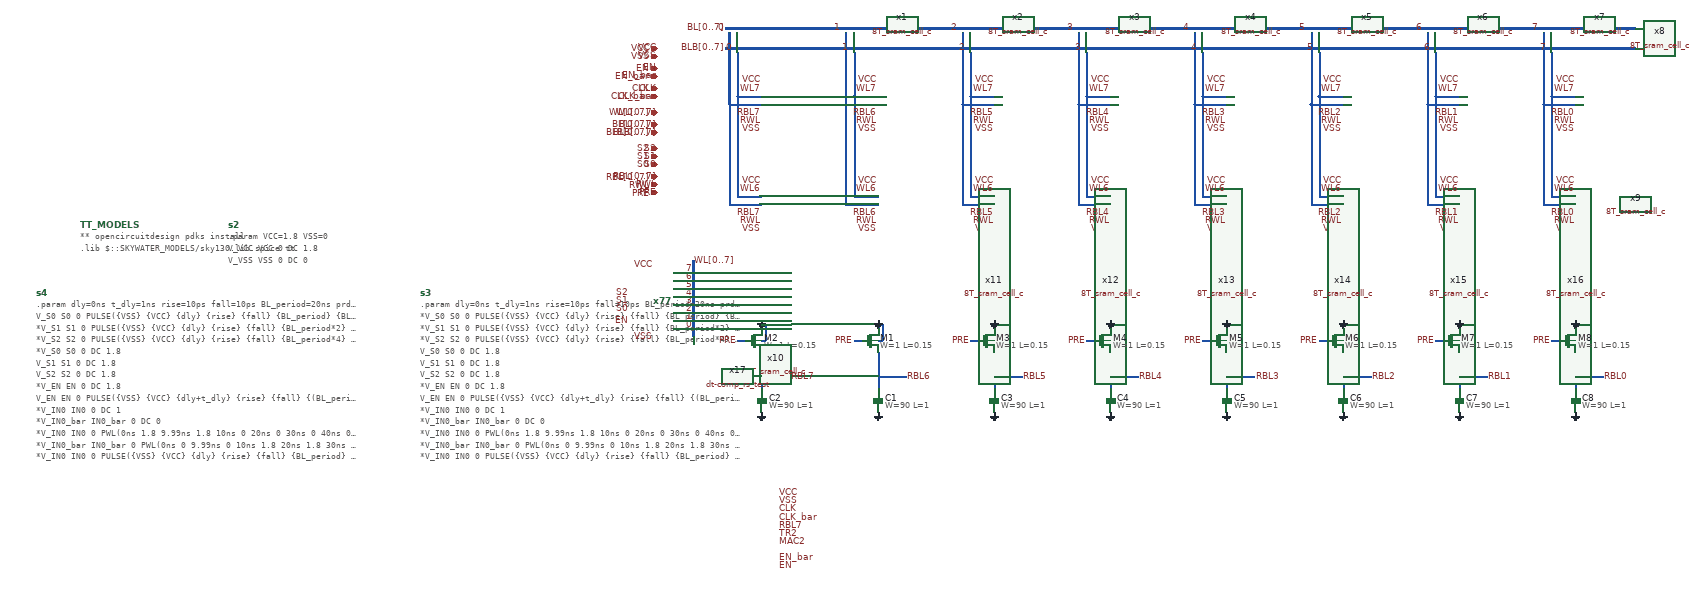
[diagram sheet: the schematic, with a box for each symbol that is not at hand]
v {xschem version=3.4.8RC file_version=1.3}
G {}
K {}
V {}
S {}
F {}
E {}
B 2 -940 -2980 -140 -2580 {flags=graph
y1=-0.027
y2=1.9
ypos1=-0.31605
ypos2=1.61095
divy=5
subdivy=1
unity=1
x1=-1.3514731e+246
x2=2.0890986e+307
divx=5
subdivx=1
xlabmag=1.0
ylabmag=1.0
dataset=-1
unitx=1
logx=0
logy=0
rawfile=$netlist_dir/write_test_row.raw
autoload=0
digital=1
legend=1
color="4 5 6 7 8 9 10 20 4 4 4 4 4 4 4 4"
node="x8.q
x7.q
x6.q
x5.q
x4.q
x3.q
x2.q
x1.q
x8.q_bar
x7.q_bar
x6.q_bar
x5.q_bar
x4.q_bar
x3.q_bar
x2.q_bar
x1.q_bar"
sim_type=tran}
B 2 -1760 -2980 -960 -2580 {flags=graph
y1=-0.027
y2=1.9
ypos1=-0.4124
ypos2=1.5146
divy=5
subdivy=1
unity=1
x1=-1.3514731e+246
x2=2.0890986e+307
divx=5
subdivx=1
xlabmag=1.0
ylabmag=1.0
dataset=-1
unitx=1
logx=0
logy=0
rawfile=$netlist_dir/write_test_row.raw
autoload=0
digital=1
color="4 5 6 7 8 9"
node="s2
s1
s0
en
pre
rwl"
hilight_wave=-1}
B 2 -1760 -2440 -960 -2040 {flags=graph
y1=-0.027
y2=1.9
ypos1=-0.027
ypos2=1.9
divy=5
subdivy=1
unity=1
x1=-1.3514731e+246
x2=2.0890986e+307
divx=5
subdivx=1
xlabmag=1.0
ylabmag=1.0
dataset=-1
unitx=1
logx=0
logy=0
rawfile=$netlist_dir/write_test_row.raw
autoload=0
digital=1
color="4 5 6 7 8 9 10 11"
node="bl7
bl6
bl5
bl4
bl3
bl2
bl1
bl0"
hilight_wave=-1}
B 2 -940 -2440 -140 -2040 {flags=graph
y1=-3.4e+249
y2=2.1e+307
ypos1=-0.027
ypos2=1.9
divy=5
subdivy=1
unity=1
x1=-1.3514731e+246
x2=2.0890986e+307
divx=5
subdivx=1
xlabmag=1.0
ylabmag=1.0
dataset=-1
unitx=1
logx=0
logy=0
rawfile=$netlist_dir/write_test_row.raw
autoload=0
digital=0
hilight_wave=2
color="4 5 6"
node="pre
rwl
rbl7"}
N 370 -1440 370 -1350 {lab=RBL7}
N 370 -1380 440 -1380 {lab=RBL7}
N 370 -1520 370 -1500 {lab=GND}
N 370 -1470 380 -1470 {lab=GND}
N 380 -1510 380 -1470 {lab=GND}
N 370 -1510 380 -1510 {lab=GND}
N 310 -1470 330 -1470 {lab=PRE}
N 280 -2250 2550 -2250 {lab=BL[0..7]
bus=true}
N 280 -2200 2550 -2200 {lab=BLB[0..7]
bus=true}
N 310 -2190 310 -2080 {lab=BLB0}
N 310 -2080 370 -2080 {lab=BLB0}
N 290 -2240 290 -2060 {lab=BL0
bus}
N 290 -2060 370 -2060 {lab=BL0}
N 600 -2190 600 -2080 {lab=BLB1}
N 600 -2080 660 -2080 {lab=BLB1}
N 580 -2240 580 -2060 {lab=BL1}
N 580 -2060 660 -2060 {lab=BL1}
N 890 -2190 890 -2080 {lab=BLB2}
N 890 -2080 950 -2080 {lab=BLB2}
N 870 -2240 870 -2060 {lab=BL2}
N 870 -2060 950 -2060 {lab=BL2}
N 1180 -2190 1180 -2080 {lab=BLB3}
N 1180 -2080 1240 -2080 {lab=BLB3}
N 1160 -2240 1160 -2060 {lab=BL3}
N 1160 -2060 1240 -2060 {lab=BL3}
N 1470 -2190 1470 -2080 {lab=BLB4}
N 1470 -2080 1530 -2080 {lab=BLB4}
N 1450 -2240 1450 -2060 {lab=BL4}
N 1450 -2060 1530 -2060 {lab=BL4}
N 1760 -2190 1760 -2080 {lab=BLB5}
N 1760 -2080 1820 -2080 {lab=BLB5}
N 1740 -2240 1740 -2060 {lab=BL5}
N 1740 -2060 1820 -2060 {lab=BL5}
N 2050 -2190 2050 -2080 {lab=BLB6}
N 2050 -2080 2110 -2080 {lab=BLB6}
N 2030 -2240 2030 -2060 {lab=BL6}
N 2030 -2060 2110 -2060 {lab=BL6}
N 2340 -2190 2340 -2080 {lab=BLB7}
N 2340 -2080 2400 -2080 {lab=BLB7}
N 2320 -2240 2320 -2060 {lab=BL7}
N 2320 -2060 2400 -2060 {lab=BL7}
N 200 -1670 200 -1480 {lab=WL[0..7]
bus=true}
N 150 -1640 190 -1640 {lab=WL7}
N 150 -1620 190 -1620 {lab=WL6}
N 150 -1600 190 -1600 {lab=WL5}
N 150 -1580 190 -1580 {lab=WL4}
N 150 -1560 190 -1560 {lab=WL3}
N 150 -1540 190 -1540 {lab=WL2}
N 150 -1520 190 -1520 {lab=WL1}
N 150 -1500 190 -1500 {lab=WL0}
N 290 -2060 290 -1810 {lab=BL0}
N 290 -1810 370 -1810 {lab=BL0}
N 310 -2080 310 -1830 {lab=BLB0}
N 310 -1830 370 -1830 {lab=BLB0}
N 580 -2060 580 -1810 {lab=BL1}
N 580 -1810 660 -1810 {lab=BL1}
N 600 -2080 600 -1830 {lab=BLB1}
N 600 -1830 660 -1830 {lab=BLB1}
N 870 -2060 870 -1810 {lab=BL2}
N 870 -1810 950 -1810 {lab=BL2}
N 890 -2080 890 -1830 {lab=BLB2}
N 890 -1830 950 -1830 {lab=BLB2}
N 1160 -2060 1160 -1810 {lab=BL3}
N 1160 -1810 1240 -1810 {lab=BL3}
N 1180 -2080 1180 -1830 {lab=BLB3}
N 1180 -1830 1240 -1830 {lab=BLB3}
N 1450 -2060 1450 -1810 {lab=BL4}
N 1450 -1810 1530 -1810 {lab=BL4}
N 1470 -2080 1470 -1830 {lab=BLB4}
N 1470 -1830 1530 -1830 {lab=BLB4}
N 1740 -2060 1740 -1810 {lab=BL5}
N 1740 -1810 1820 -1810 {lab=BL5}
N 1760 -2080 1760 -1830 {lab=BLB5}
N 1760 -1830 1820 -1830 {lab=BLB5}
N 2030 -2060 2030 -1810 {lab=BL6}
N 2030 -1810 2110 -1810 {lab=BL6}
N 2050 -2080 2050 -1830 {lab=BLB6}
N 2050 -1830 2110 -1830 {lab=BLB6}
N 2320 -2060 2320 -1810 {lab=BL7}
N 2320 -1810 2400 -1810 {lab=BL7}
N 2340 -2080 2340 -1830 {lab=BLB7}
N 2340 -1830 2400 -1830 {lab=BLB7}
N 660 -1440 660 -1350 {lab=RBL6}
N 660 -1380 730 -1380 {lab=RBL6}
N 660 -1520 660 -1500 {lab=GND}
N 660 -1470 670 -1470 {lab=GND}
N 670 -1510 670 -1470 {lab=GND}
N 660 -1510 670 -1510 {lab=GND}
N 600 -1470 620 -1470 {lab=PRE}
N 950 -1440 950 -1350 {lab=RBL5}
N 950 -1380 1020 -1380 {lab=RBL5}
N 950 -1520 950 -1500 {lab=GND}
N 950 -1470 960 -1470 {lab=GND}
N 960 -1510 960 -1470 {lab=GND}
N 950 -1510 960 -1510 {lab=GND}
N 890 -1470 910 -1470 {lab=PRE}
N 1240 -1440 1240 -1350 {lab=RBL4}
N 1240 -1380 1310 -1380 {lab=RBL4}
N 1240 -1520 1240 -1500 {lab=GND}
N 1240 -1470 1250 -1470 {lab=GND}
N 1250 -1510 1250 -1470 {lab=GND}
N 1240 -1510 1250 -1510 {lab=GND}
N 1180 -1470 1200 -1470 {lab=PRE}
N 1530 -1440 1530 -1350 {lab=RBL3}
N 1530 -1380 1600 -1380 {lab=RBL3}
N 1530 -1520 1530 -1500 {lab=GND}
N 1530 -1470 1540 -1470 {lab=GND}
N 1540 -1510 1540 -1470 {lab=GND}
N 1530 -1510 1540 -1510 {lab=GND}
N 1470 -1470 1490 -1470 {lab=PRE}
N 1820 -1440 1820 -1350 {lab=RBL2}
N 1820 -1380 1890 -1380 {lab=RBL2}
N 1820 -1520 1820 -1500 {lab=GND}
N 1820 -1470 1830 -1470 {lab=GND}
N 1830 -1510 1830 -1470 {lab=GND}
N 1820 -1510 1830 -1510 {lab=GND}
N 1760 -1470 1780 -1470 {lab=PRE}
N 2110 -1440 2110 -1350 {lab=RBL1}
N 2110 -1380 2180 -1380 {lab=RBL1}
N 2110 -1520 2110 -1500 {lab=GND}
N 2110 -1470 2120 -1470 {lab=GND}
N 2120 -1510 2120 -1470 {lab=GND}
N 2110 -1510 2120 -1510 {lab=GND}
N 2050 -1470 2070 -1470 {lab=PRE}
N 2400 -1440 2400 -1350 {lab=RBL0}
N 2400 -1380 2470 -1380 {lab=RBL0}
N 2400 -1520 2400 -1500 {lab=GND}
N 2400 -1470 2410 -1470 {lab=GND}
N 2410 -1510 2410 -1470 {lab=GND}
N 2400 -1510 2410 -1510 {lab=GND}
N 2340 -1470 2360 -1470 {lab=PRE}
C {iopin.sym} 110 -2040 0 0 {name=p7 lab=WL[0..7]}
C {lab_pin.sym} 110 -2040 0 0 {name=p18 sig_type=std_logic lab=WL[0..7]}
C {lab_pin.sym} 370 -2100 0 0 {name=p1 sig_type=std_logic lab=WL7}
C {lab_pin.sym} 370 -2000 0 0 {name=p43 sig_type=std_logic lab=VSS}
C {lab_pin.sym} 370 -2120 0 0 {name=p51 sig_type=std_logic lab=VCC}
C {code.sym} -1330 -1760 0 0 {
name=TT_MODELS
only_toplevel=true
format="tcleval( @value )"
spice_ignore=false
value="
** opencircuitdesign pdks install
.lib $::SKYWATER_MODELS/sky130.lib.spice tt
"
spice_ignore=false
      }
C {code_shown.sym} -960 -1760 0 1 {name=s2 only_toplevel=false spice_ignore=false value=
"
.param VCC=1.8 VSS=0

V_VCC VCC 0 DC 1.8
V_VSS VSS 0 DC 0
"}
C {iopin.sym} 110 -1950 0 0 {name=p69 lab=S2}
C {iopin.sym} 110 -1930 0 0 {name=p70 lab=S1}
C {iopin.sym} 110 -1910 0 0 {name=p71 lab=S0}
C {lab_pin.sym} 110 -1950 0 0 {name=p72 sig_type=std_logic lab=S2}
C {lab_pin.sym} 110 -1930 0 0 {name=p73 sig_type=std_logic lab=S1}
C {lab_pin.sym} 110 -1910 0 0 {name=p74 sig_type=std_logic lab=S0}
C {iopin.sym} 110 -2200 0 0 {name=p78 lab=VCC}
C {iopin.sym} 110 -2180 0 0 {name=p79 lab=VSS}
C {lab_pin.sym} 110 -2180 0 0 {name=p80 sig_type=std_logic lab=VSS}
C {lab_pin.sym} 110 -2200 0 0 {name=p81 sig_type=std_logic lab=VCC}
C {iopin.sym} 110 -2150 0 0 {name=p82 lab=EN}
C {lab_pin.sym} 110 -2150 0 0 {name=p83 sig_type=std_logic lab=EN}
C {code_shown.sym} -480 -1590 0 1 {name=s3 only_toplevel=false spice_ignore=true value=
"
.param dly=0ns t_dly=1ns rise=10ps fall=10ps BL_period=20ns prds=8 pre_time=6ns read_time=2ns write_delay=10ns 


*V_S0 S0 0 PULSE(\{VSS\} \{VCC\} \{dly\} \{rise\} \{fall\} \{BL_period\} \{BL_period*2\} \{prds\})
*V_S1 S1 0 PULSE(\{VSS\} \{VCC\} \{dly\} \{rise\} \{fall\} \{BL_period*2\} \{BL_period*4\} \{prds\})
*V_S2 S2 0 PULSE(\{VSS\} \{VCC\} \{dly\} \{rise\} \{fall\} \{BL_period*4\} \{BL_period*8\} \{prds\})

V_S0 S0 0 DC 1.8
V_S1 S1 0 DC 1.8
V_S2 S2 0 DC 1.8

*V_EN EN 0 DC 1.8
V_EN EN 0 PULSE(\{VSS\} \{VCC\} \{dly+t_dly\} \{rise\} \{fall\} \{(BL_period/2)-t_dly*2\} \{BL_period\} \{prds\})

*V_IN0 IN0 0 DC 1
*V_IN0_bar IN0_bar 0 DC 0
*V_IN0 IN0 0 PWL(0ns 1.8 9.99ns 1.8 10ns 0 20ns 0 30ns 0 40ns 0 50ns 0 60ns 0 69.99ns 0 70ns 1.8)
*V_IN0_bar IN0_bar 0 PWL(0ns 0 9.99ns 0 10ns 1.8 20ns 1.8 30ns 1.8 40ns 1.8 50ns 1.8 60ns 1.8 69.99ns 1.8 70ns 0)
*V_IN0 IN0 0 PULSE(\{VSS\} \{VCC\} \{dly\} \{rise\} \{fall\} \{BL_period\} \{BL_period*2\} \{prds\})
*V_IN0_bar IN0_bar 0 PULSE(\{VCC\} \{VSS\} \{dly\} \{rise\} \{fall\} \{BL_period\} \{BL_period*2\} \{prds\})

V_BL0 BLB0 0 PULSE(\{VSS\} \{VCC\} \{dly\} \{rise\} \{fall\} \{BL_period\} \{BL_period*2\} \{prds\})
V_BLB0 BL0 0 PULSE(\{VCC\} \{VSS\} \{dly\} \{rise\} \{fall\} \{BL_period\} \{BL_period*2\} \{prds\})

V_BL1 BLB1 0 PULSE(\{VSS\} \{VCC\} \{dly\} \{rise\} \{fall\} \{BL_period*2\} \{BL_period*4\} \{prds\})
V_BLB1 BL1 0 PULSE(\{VCC\} \{VSS\} \{dly\} \{rise\} \{fall\} \{BL_period*2\} \{BL_period*4\} \{prds\})

V_BL2 BLB2 0 PULSE(\{VSS\} \{VCC\} \{dly\} \{rise\} \{fall\} \{BL_period*4\} \{BL_period*8\} \{prds\})
V_BLB2 BL2 0 PULSE(\{VCC\} \{VSS\} \{dly\} \{rise\} \{fall\} \{BL_period*4\} \{BL_period*8\} \{prds\})

V_BL3 BLB3 0 PULSE(\{VSS\} \{VCC\} \{dly\} \{rise\} \{fall\} \{BL_period*8\} \{BL_period*16\} \{prds\})
V_BLB3 BL3 0 PULSE(\{VCC\} \{VSS\} \{dly\} \{rise\} \{fall\} \{BL_period*8\} \{BL_period*16\} \{prds\})

V_BL4 BLB4 0 PULSE(\{VSS\} \{VCC\} \{dly\} \{rise\} \{fall\} \{BL_period*16\} \{BL_period*32\} \{prds\})
V_BLB4 BL4 0 PULSE(\{VCC\} \{VSS\} \{dly\} \{rise\} \{fall\} \{BL_period*16\} \{BL_period*32\} \{prds\})

V_BL5 BLB5 0 PULSE(\{VSS\} \{VCC\} \{dly\} \{rise\} \{fall\} \{BL_period*32\} \{BL_period*64\} \{prds\})
V_BLB5 BL5 0 PULSE(\{VCC\} \{VSS\} \{dly\} \{rise\} \{fall\} \{BL_period*32\} \{BL_period*64\} \{prds\})

V_BL6 BLB6 0 PULSE(\{VSS\} \{VCC\} \{dly\} \{rise\} \{fall\} \{BL_period*64\} \{BL_period*128\} \{prds\})
V_BLB6 BL6 0 PULSE(\{VCC\} \{VSS\} \{dly\} \{rise\} \{fall\} \{BL_period*64\} \{BL_period*128\} \{prds\})

V_BL7 BLB7 0 PULSE(\{VSS\} \{VCC\} \{dly\} \{rise\} \{fall\} \{BL_period*128\} \{BL_period*256\} \{prds\})
V_BLB7 BL7 0 PULSE(\{VCC\} \{VSS\} \{dly\} \{rise\} \{fall\} \{BL_period*128\} \{BL_period*256\} \{prds\})



*V_RWL RWL 0 DC 1.8
*V_RBL RBL 0 DC 0
*V_RWL RWL 0 PULSE(\{VCC\} \{VSS\} \{write_delay+t_dly+pre_time+t_dly\} \{rise\} \{fall\} \{read_time\} \{BL_period\} \{prds\})
*V_PRE PRE 0 PULSE(\{VSS\} \{VCC\} \{write_delay+t_dly\} \{rise\} \{fall\} \{pre_time\} \{BL_period\} \{prds\})
V_RWL RWL 0 PULSE(\{VCC\} \{VSS\} \{dly + BL_period/2 + 7ns\} \{rise\} \{fall\} \{read_time\} \{BL_period\} \{prds*2\})
V_PRE PRE 0 PULSE(\{VSS\} \{VCC\} \{dly + BL_period/2\} \{rise\} \{fall\} \{pre_time\} \{BL_period\} \{prds*2\})

.tran 0.01ns \{BL_period*2*10\}
.save all

.control
run
plot Y0 Y1+2 Y2+4 Y3+6 Y4+8 Y5+10 Y6+12 Y7+14
plot EN
plot I0 I1+2 I2+4
.endc
"}
C {launcher.sym} -840 -2540 0 0 {name=h5
descr="load waves" 
tclcommand="xschem raw_read $netlist_dir/write_test_row.raw tran"
}
C {8T_sram_cell_c.sym} 2550 -2060 0 1 {name=x8}
C {lab_pin.sym} 370 -2020 0 0 {name=p87 sig_type=std_logic lab=RWL}
C {lab_pin.sym} 370 -2040 0 0 {name=p103 sig_type=std_logic lab=RBL7}
C {iopin.sym} 110 -1880 0 0 {name=p89 lab=RBL[0..7]}
C {iopin.sym} 110 -1860 0 0 {name=p90 lab=RWL}
C {lab_pin.sym} 110 -1880 0 0 {name=p91 sig_type=std_logic lab=RBL[0..7]}
C {lab_pin.sym} 110 -1860 0 0 {name=p92 sig_type=std_logic lab=RWL}
C {sky130_fd_pr/cap_mim_m3_1.sym} 370 -1320 0 0 {name=C2 model=cap_mim_m3_1 W=90 L=1 MF=1 spiceprefix=X}
C {gnd.sym} 370 -1520 2 0 {name=l1 lab=GND}
C {sky130_fd_pr/nfet_01v8.sym} 350 -1470 2 1 {name=M2
W=1
L=0.15
nf=1 
mult=1
ad="expr('int((@nf + 1)/2) * @W / @nf * 0.29')"
pd="expr('2*int((@nf + 1)/2) * (@W / @nf + 0.29)')"
as="expr('int((@nf + 2)/2) * @W / @nf * 0.29')"
ps="expr('2*int((@nf + 2)/2) * (@W / @nf + 0.29)')"
nrd="expr('0.29 / @W ')" nrs="expr('0.29 / @W ')"
sa=0 sb=0 sd=0
model=nfet_01v8
spiceprefix=X
}
C {gnd.sym} 370 -1290 0 1 {name=l10 lab=GND}
C {iopin.sym} 110 -1840 0 0 {name=p93 lab=PRE}
C {lab_pin.sym} 110 -1840 0 0 {name=p95 sig_type=std_logic lab=PRE}
C {lab_pin.sym} 310 -1470 0 0 {name=p96 sig_type=std_logic lab=PRE}
C {lab_pin.sym} 660 -2100 0 0 {name=p2 sig_type=std_logic lab=WL7}
C {lab_pin.sym} 660 -2000 0 0 {name=p5 sig_type=std_logic lab=VSS}
C {lab_pin.sym} 660 -2120 0 0 {name=p6 sig_type=std_logic lab=VCC}
C {8T_sram_cell_c.sym} 520 -2060 0 1 {name=x1}
C {lab_pin.sym} 660 -2020 0 0 {name=p15 sig_type=std_logic lab=RWL}
C {lab_pin.sym} 660 -2040 0 0 {name=p16 sig_type=std_logic lab=RBL6}
C {lab_pin.sym} 950 -2100 0 0 {name=p28 sig_type=std_logic lab=WL7}
C {lab_pin.sym} 950 -2000 0 0 {name=p31 sig_type=std_logic lab=VSS}
C {lab_pin.sym} 950 -2120 0 0 {name=p32 sig_type=std_logic lab=VCC}
C {8T_sram_cell_c.sym} 810 -2060 0 1 {name=x2}
C {lab_pin.sym} 950 -2020 0 0 {name=p33 sig_type=std_logic lab=RWL}
C {lab_pin.sym} 950 -2040 0 0 {name=p34 sig_type=std_logic lab=RBL5}
C {lab_pin.sym} 1240 -2100 0 0 {name=p36 sig_type=std_logic lab=WL7}
C {lab_pin.sym} 1240 -2000 0 0 {name=p39 sig_type=std_logic lab=VSS}
C {lab_pin.sym} 1240 -2120 0 0 {name=p40 sig_type=std_logic lab=VCC}
C {8T_sram_cell_c.sym} 1100 -2060 0 1 {name=x3}
C {lab_pin.sym} 1240 -2020 0 0 {name=p41 sig_type=std_logic lab=RWL}
C {lab_pin.sym} 1240 -2040 0 0 {name=p42 sig_type=std_logic lab=RBL4}
C {lab_pin.sym} 1530 -2100 0 0 {name=p44 sig_type=std_logic lab=WL7}
C {lab_pin.sym} 1530 -2000 0 0 {name=p47 sig_type=std_logic lab=VSS}
C {lab_pin.sym} 1530 -2120 0 0 {name=p48 sig_type=std_logic lab=VCC}
C {8T_sram_cell_c.sym} 1390 -2060 0 1 {name=x4}
C {lab_pin.sym} 1530 -2020 0 0 {name=p49 sig_type=std_logic lab=RWL}
C {lab_pin.sym} 1530 -2040 0 0 {name=p52 sig_type=std_logic lab=RBL3}
C {lab_pin.sym} 1820 -2100 0 0 {name=p53 sig_type=std_logic lab=WL7}
C {lab_pin.sym} 1820 -2000 0 0 {name=p56 sig_type=std_logic lab=VSS}
C {lab_pin.sym} 1820 -2120 0 0 {name=p57 sig_type=std_logic lab=VCC}
C {8T_sram_cell_c.sym} 1680 -2060 0 1 {name=x5}
C {lab_pin.sym} 1820 -2020 0 0 {name=p58 sig_type=std_logic lab=RWL}
C {lab_pin.sym} 1820 -2040 0 0 {name=p88 sig_type=std_logic lab=RBL2}
C {lab_pin.sym} 2110 -2100 0 0 {name=p97 sig_type=std_logic lab=WL7}
C {lab_pin.sym} 2110 -2000 0 0 {name=p100 sig_type=std_logic lab=VSS}
C {lab_pin.sym} 2110 -2120 0 0 {name=p101 sig_type=std_logic lab=VCC}
C {8T_sram_cell_c.sym} 1970 -2060 0 1 {name=x6}
C {lab_pin.sym} 2110 -2020 0 0 {name=p104 sig_type=std_logic lab=RWL}
C {lab_pin.sym} 2110 -2040 0 0 {name=p105 sig_type=std_logic lab=RBL1}
C {lab_pin.sym} 2400 -2100 0 0 {name=p106 sig_type=std_logic lab=WL7}
C {lab_pin.sym} 2400 -2000 0 0 {name=p109 sig_type=std_logic lab=VSS}
C {lab_pin.sym} 2400 -2120 0 0 {name=p110 sig_type=std_logic lab=VCC}
C {8T_sram_cell_c.sym} 2260 -2060 0 1 {name=x7}
C {lab_pin.sym} 2400 -2020 0 0 {name=p111 sig_type=std_logic lab=RWL}
C {lab_pin.sym} 2400 -2040 0 0 {name=p112 sig_type=std_logic lab=RBL0}
C {iopin.sym} 110 -2010 0 0 {name=p17 lab=BL[0..7]}
C {lab_pin.sym} 110 -2010 0 0 {name=p26 sig_type=std_logic lab=BL[0..7]}
C {iopin.sym} 110 -1990 0 0 {name=p59 lab=BLB[0..7]}
C {lab_pin.sym} 110 -1990 0 0 {name=p60 sig_type=std_logic lab=BLB[0..7]}
C {logic gates/decoder.sym} 100 -1570 0 0 {name=x77}
C {lab_pin.sym} 40 -1590 0 0 {name=p75 sig_type=std_logic lab=S2}
C {lab_pin.sym} 40 -1570 0 0 {name=p76 sig_type=std_logic lab=S1}
C {lab_pin.sym} 40 -1550 0 0 {name=p77 sig_type=std_logic lab=S0}
C {lab_pin.sym} 40 -1520 0 0 {name=p84 sig_type=std_logic lab=EN}
C {lab_pin.sym} 100 -1660 0 0 {name=p85 sig_type=std_logic lab=VCC}
C {lab_pin.sym} 100 -1480 0 0 {name=p86 sig_type=std_logic lab=VSS}
C {bus_tap.sym} 280 -2250 1 0 {name=l2 lab=0}
C {lab_pin.sym} 280 -2250 0 0 {name=p3 sig_type=std_logic lab=BL[0..7]}
C {lab_pin.sym} 280 -2200 0 0 {name=p4 sig_type=std_logic lab=BLB[0..7]}
C {bus_tap.sym} 300 -2200 1 0 {name=l3 lab=0}
C {bus_tap.sym} 570 -2250 1 0 {name=l4 lab=1}
C {bus_tap.sym} 590 -2200 1 0 {name=l5 lab=1}
C {bus_tap.sym} 860 -2250 1 0 {name=l6 lab=2}
C {bus_tap.sym} 880 -2200 1 0 {name=l7 lab=2}
C {bus_tap.sym} 1150 -2250 1 0 {name=l8 lab=3}
C {bus_tap.sym} 1170 -2200 1 0 {name=l9 lab=3}
C {bus_tap.sym} 1730 -2250 1 0 {name=l11 lab=5}
C {bus_tap.sym} 1750 -2200 1 0 {name=l12 lab=5}
C {bus_tap.sym} 2020 -2250 1 0 {name=l13 lab=6}
C {bus_tap.sym} 2040 -2200 1 0 {name=l14 lab=6}
C {bus_tap.sym} 2310 -2250 1 0 {name=l15 lab=7}
C {bus_tap.sym} 2330 -2200 1 0 {name=l16 lab=7}
C {bus_tap.sym} 1440 -2250 1 0 {name=l17 lab=4}
C {bus_tap.sym} 1460 -2200 1 0 {name=l18 lab=4}
C {code_shown.sym} -1440 -1590 0 1 {name=s4 only_toplevel=false spice_ignore=false value=
"
.param dly=0ns t_dly=1ns rise=10ps fall=10ps BL_period=20ns prds=10 pre_time=6ns read_time=2ns write_delay=10ns 


V_S0 S0 0 PULSE(\{VSS\} \{VCC\} \{dly\} \{rise\} \{fall\} \{BL_period\} \{BL_period*2\} \{prds\})
*V_S1 S1 0 PULSE(\{VSS\} \{VCC\} \{dly\} \{rise\} \{fall\} \{BL_period*2\} \{BL_period*4\} \{prds\})
*V_S2 S2 0 PULSE(\{VSS\} \{VCC\} \{dly\} \{rise\} \{fall\} \{BL_period*4\} \{BL_period*8\} \{prds\})

*V_S0 S0 0 DC 1.8
V_S1 S1 0 DC 1.8
V_S2 S2 0 DC 1.8

*V_EN EN 0 DC 1.8
V_EN EN 0 PULSE(\{VSS\} \{VCC\} \{dly+t_dly\} \{rise\} \{fall\} \{(BL_period/2)-t_dly*2\} \{BL_period\} \{prds\})

*V_IN0 IN0 0 DC 1
*V_IN0_bar IN0_bar 0 DC 0
*V_IN0 IN0 0 PWL(0ns 1.8 9.99ns 1.8 10ns 0 20ns 0 30ns 0 40ns 0 50ns 0 60ns 0 69.99ns 0 70ns 1.8)
*V_IN0_bar IN0_bar 0 PWL(0ns 0 9.99ns 0 10ns 1.8 20ns 1.8 30ns 1.8 40ns 1.8 50ns 1.8 60ns 1.8 69.99ns 1.8 70ns 0)
*V_IN0 IN0 0 PULSE(\{VSS\} \{VCC\} \{dly\} \{rise\} \{fall\} \{BL_period\} \{BL_period*2\} \{prds\})
*V_IN0_bar IN0_bar 0 PULSE(\{VCC\} \{VSS\} \{dly\} \{rise\} \{fall\} \{BL_period\} \{BL_period*2\} \{prds\})

V_BL0 BLB0 0 PWL(0ns 1.8 20ns 1.8 40ns 1.8 59.99ns 1.8 60ns 0 80ns 0 99.99ns 0 100ns 1.8 119.99ns 1.8 120ns 0 140ns 0)
V_BLB0 BL0 0 PWL(0ns 0 20ns 0 40ns 0 59.99ns 0 60ns 1.8 80ns 1.8 99.99ns 1.8 100ns 0 119.99ns 0 120ns 1.8 140ns 1.8)

V_BL1 BLB1 0 PWL(0ns 1.8 20ns 1.8 40ns 1.8 59.99ns 1.8 60ns 0 80ns 0 99.99ns 0 100ns 1.8 119.99ns 1.8 120ns 0 140ns 0)
V_BLB1 BL1 0 PWL(0ns 0 20ns 0 40ns 0 59.99ns 0 60ns 1.8 80ns 1.8 99.99ns 1.8 100ns 0 119.99ns 0 120ns 1.8 140ns 1.8)

V_BL2 BLB2 0 PWL(0ns 1.8 20ns 1.8 40ns 1.8 59.99ns 1.8 60ns 0 80ns 0 99.99ns 0 100ns 1.8 119.99ns 1.8 120ns 0 140ns 0)
V_BLB2 BL2 0 PWL(0ns 0 20ns 0 40ns 0 59.99ns 0 60ns 1.8 80ns 1.8 99.99ns 1.8 100ns 0 119.99ns 0 120ns 1.8 140ns 1.8)

V_BL3 BLB3 0 PWL(0ns 1.8 20ns 1.8 40ns 1.8 59.99ns 1.8 60ns 0 80ns 0 99.99ns 0 100ns 1.8 119.99ns 1.8 120ns 0 140ns 0)
V_BLB3 BL3 0 PWL(0ns 0 20ns 0 40ns 0 59.99ns 0 60ns 1.8 80ns 1.8 99.99ns 1.8 100ns 0 119.99ns 0 120ns 1.8 140ns 1.8)

V_BL4 BLB4 0 PWL(0ns 1.8 20ns 1.8 40ns 1.8 59.99ns 1.8 60ns 0 80ns 0 99.99ns 0 100ns 1.8 119.99ns 1.8 120ns 0 140ns 0)
V_BLB4 BL4 0 PWL(0ns 0 20ns 0 40ns 0 59.99ns 0 60ns 1.8 80ns 1.8 99.99ns 1.8 100ns 0 119.99ns 0 120ns 1.8 140ns 1.8)

V_BL5 BLB5 0 PWL(0ns 1.8 20ns 1.8 40ns 1.8 59.99ns 1.8 60ns 0 80ns 0 99.99ns 0 100ns 1.8 119.99ns 1.8 120ns 0 140ns 0)
V_BLB5 BL5 0 PWL(0ns 0 20ns 0 40ns 0 59.99ns 0 60ns 1.8 80ns 1.8 99.99ns 1.8 100ns 0 119.99ns 0 120ns 1.8 140ns 1.8)

V_BL6 BLB6 0 PWL(0ns 1.8 20ns 1.8 40ns 1.8 59.99ns 1.8 60ns 0 80ns 0 99.99ns 0 100ns 1.8 119.99ns 1.8 120ns 0 140ns 0)
V_BLB6 BL6 0 PWL(0ns 0 20ns 0 40ns 0 59.99ns 0 60ns 1.8 80ns 1.8 99.99ns 1.8 100ns 0 119.99ns 0 120ns 1.8 140ns 1.8)

V_BL7 BLB7 0 PWL(0ns 1.8 20ns 1.8 40ns 1.8 59.99ns 1.8 60ns 0 80ns 0 99.99ns 0 100ns 1.8 119.99ns 1.8 120ns 0 140ns 0)
V_BLB7 BL7 0 PWL(0ns 0 20ns 0 40ns 0 59.99ns 0 60ns 1.8 80ns 1.8 99.99ns 1.8 100ns 0 119.99ns 0 120ns 1.8 140ns 1.8)



*V_RWL RWL 0 DC 1.8
*V_RBL RBL 0 DC 0
*V_RWL RWL 0 PULSE(\{VCC\} \{VSS\} \{write_delay+t_dly+pre_time+t_dly\} \{rise\} \{fall\} \{read_time\} \{BL_period\} \{prds\})
*V_PRE PRE 0 PULSE(\{VSS\} \{VCC\} \{write_delay+t_dly\} \{rise\} \{fall\} \{pre_time\} \{BL_period\} \{prds\})
V_RWL RWL 0 PULSE(\{VCC\} \{VSS\} \{dly + BL_period/2 + 7ns\} \{rise\} \{fall\} \{read_time\} \{BL_period\} \{prds\})
V_PRE PRE 0 PULSE(\{VSS\} \{VCC\} \{dly + BL_period/2\} \{rise\} \{fall\} \{pre_time\} \{BL_period\} \{prds\})

.tran 0.01ns \{BL_period*10\}
.save all

.control
run
plot Y0 Y1+2 Y2+4 Y3+6 Y4+8 Y5+10 Y6+12 Y7+14
plot EN
plot I0 I1+2 I2+4
.endc
"}
C {lab_pin.sym} 200 -1670 0 1 {name=p8 sig_type=std_logic lab=WL[0..7]}
C {bus_tap.sym} 200 -1590 3 1 {name=l21 lab=4}
C {bus_tap.sym} 200 -1570 3 1 {name=l22 lab=3}
C {bus_tap.sym} 200 -1550 3 1 {name=l23 lab=2}
C {bus_tap.sym} 200 -1510 3 1 {name=l24 lab=0}
C {bus_tap.sym} 200 -1530 3 1 {name=l25 lab=1}
C {bus_tap.sym} 200 -1610 3 1 {name=l19 lab=5}
C {bus_tap.sym} 200 -1630 3 1 {name=l20 lab=6}
C {bus_tap.sym} 200 -1650 3 1 {name=l26 lab=7}
C {lab_pin.sym} 370 -1750 0 0 {name=p9 sig_type=std_logic lab=VSS}
C {8T_sram_cell_c.sym} 2550 -1810 0 1 {name=x9}
C {lab_pin.sym} 370 -1770 0 0 {name=p10 sig_type=std_logic lab=RWL}
C {lab_pin.sym} 370 -1790 0 0 {name=p11 sig_type=std_logic lab=RBL7}
C {lab_pin.sym} 660 -1750 0 0 {name=p12 sig_type=std_logic lab=VSS}
C {8T_sram_cell_c.sym} 520 -1810 0 1 {name=x10}
C {lab_pin.sym} 660 -1770 0 0 {name=p13 sig_type=std_logic lab=RWL}
C {lab_pin.sym} 660 -1790 0 0 {name=p14 sig_type=std_logic lab=RBL6}
C {lab_pin.sym} 950 -1750 0 0 {name=p19 sig_type=std_logic lab=VSS}
C {8T_sram_cell_c.sym} 810 -1810 0 1 {name=x11}
C {lab_pin.sym} 950 -1770 0 0 {name=p20 sig_type=std_logic lab=RWL}
C {lab_pin.sym} 950 -1790 0 0 {name=p21 sig_type=std_logic lab=RBL5}
C {lab_pin.sym} 1240 -1750 0 0 {name=p22 sig_type=std_logic lab=VSS}
C {8T_sram_cell_c.sym} 1100 -1810 0 1 {name=x12}
C {lab_pin.sym} 1240 -1770 0 0 {name=p23 sig_type=std_logic lab=RWL}
C {lab_pin.sym} 1240 -1790 0 0 {name=p24 sig_type=std_logic lab=RBL4}
C {lab_pin.sym} 1530 -1750 0 0 {name=p25 sig_type=std_logic lab=VSS}
C {8T_sram_cell_c.sym} 1390 -1810 0 1 {name=x13}
C {lab_pin.sym} 1530 -1770 0 0 {name=p27 sig_type=std_logic lab=RWL}
C {lab_pin.sym} 1530 -1790 0 0 {name=p29 sig_type=std_logic lab=RBL3}
C {lab_pin.sym} 1820 -1750 0 0 {name=p30 sig_type=std_logic lab=VSS}
C {8T_sram_cell_c.sym} 1680 -1810 0 1 {name=x14}
C {lab_pin.sym} 1820 -1770 0 0 {name=p35 sig_type=std_logic lab=RWL}
C {lab_pin.sym} 1820 -1790 0 0 {name=p37 sig_type=std_logic lab=RBL2}
C {lab_pin.sym} 2110 -1750 0 0 {name=p38 sig_type=std_logic lab=VSS}
C {8T_sram_cell_c.sym} 1970 -1810 0 1 {name=x15}
C {lab_pin.sym} 2110 -1770 0 0 {name=p45 sig_type=std_logic lab=RWL}
C {lab_pin.sym} 2110 -1790 0 0 {name=p46 sig_type=std_logic lab=RBL1}
C {lab_pin.sym} 2400 -1750 0 0 {name=p54 sig_type=std_logic lab=VSS}
C {8T_sram_cell_c.sym} 2260 -1810 0 1 {name=x16}
C {lab_pin.sym} 2400 -1770 0 0 {name=p55 sig_type=std_logic lab=RWL}
C {lab_pin.sym} 2400 -1790 0 0 {name=p61 sig_type=std_logic lab=RBL0}
C {lab_pin.sym} 370 -1870 0 0 {name=p62 sig_type=std_logic lab=VCC}
C {lab_pin.sym} 660 -1870 0 0 {name=p63 sig_type=std_logic lab=VCC}
C {lab_pin.sym} 950 -1870 0 0 {name=p64 sig_type=std_logic lab=VCC}
C {lab_pin.sym} 1240 -1870 0 0 {name=p65 sig_type=std_logic lab=VCC}
C {lab_pin.sym} 1530 -1870 0 0 {name=p66 sig_type=std_logic lab=VCC}
C {lab_pin.sym} 1820 -1870 0 0 {name=p67 sig_type=std_logic lab=VCC}
C {lab_pin.sym} 2110 -1870 0 0 {name=p68 sig_type=std_logic lab=VCC}
C {lab_pin.sym} 2400 -1870 0 0 {name=p98 sig_type=std_logic lab=VCC}
C {lab_pin.sym} 370 -1850 0 0 {name=p107 sig_type=std_logic lab=WL6}
C {lab_pin.sym} 660 -1850 0 0 {name=p108 sig_type=std_logic lab=WL6}
C {lab_pin.sym} 950 -1850 0 0 {name=p113 sig_type=std_logic lab=WL6}
C {lab_pin.sym} 1240 -1850 0 0 {name=p114 sig_type=std_logic lab=WL6}
C {lab_pin.sym} 1530 -1850 0 0 {name=p115 sig_type=std_logic lab=WL6}
C {lab_pin.sym} 1820 -1850 0 0 {name=p116 sig_type=std_logic lab=WL6}
C {lab_pin.sym} 2110 -1850 0 0 {name=p117 sig_type=std_logic lab=WL6}
C {lab_pin.sym} 2400 -1850 0 0 {name=p118 sig_type=std_logic lab=WL6}
C {sky130_fd_pr/cap_mim_m3_1.sym} 660 -1320 0 0 {name=C1 model=cap_mim_m3_1 W=90 L=1 MF=1 spiceprefix=X}
C {gnd.sym} 660 -1520 2 0 {name=l27 lab=GND}
C {sky130_fd_pr/nfet_01v8.sym} 640 -1470 2 1 {name=M1
W=1
L=0.15
nf=1 
mult=1
ad="expr('int((@nf + 1)/2) * @W / @nf * 0.29')"
pd="expr('2*int((@nf + 1)/2) * (@W / @nf + 0.29)')"
as="expr('int((@nf + 2)/2) * @W / @nf * 0.29')"
ps="expr('2*int((@nf + 2)/2) * (@W / @nf + 0.29)')"
nrd="expr('0.29 / @W ')" nrs="expr('0.29 / @W ')"
sa=0 sb=0 sd=0
model=nfet_01v8
spiceprefix=X
}
C {gnd.sym} 660 -1290 0 1 {name=l28 lab=GND}
C {lab_pin.sym} 600 -1470 0 0 {name=p99 sig_type=std_logic lab=PRE}
C {sky130_fd_pr/cap_mim_m3_1.sym} 950 -1320 0 0 {name=C3 model=cap_mim_m3_1 W=90 L=1 MF=1 spiceprefix=X}
C {gnd.sym} 950 -1520 2 0 {name=l29 lab=GND}
C {sky130_fd_pr/nfet_01v8.sym} 930 -1470 2 1 {name=M3
W=1
L=0.15
nf=1 
mult=1
ad="expr('int((@nf + 1)/2) * @W / @nf * 0.29')"
pd="expr('2*int((@nf + 1)/2) * (@W / @nf + 0.29)')"
as="expr('int((@nf + 2)/2) * @W / @nf * 0.29')"
ps="expr('2*int((@nf + 2)/2) * (@W / @nf + 0.29)')"
nrd="expr('0.29 / @W ')" nrs="expr('0.29 / @W ')"
sa=0 sb=0 sd=0
model=nfet_01v8
spiceprefix=X
}
C {gnd.sym} 950 -1290 0 1 {name=l30 lab=GND}
C {lab_pin.sym} 890 -1470 0 0 {name=p119 sig_type=std_logic lab=PRE}
C {sky130_fd_pr/cap_mim_m3_1.sym} 1240 -1320 0 0 {name=C4 model=cap_mim_m3_1 W=90 L=1 MF=1 spiceprefix=X}
C {gnd.sym} 1240 -1520 2 0 {name=l31 lab=GND}
C {sky130_fd_pr/nfet_01v8.sym} 1220 -1470 2 1 {name=M4
W=1
L=0.15
nf=1 
mult=1
ad="expr('int((@nf + 1)/2) * @W / @nf * 0.29')"
pd="expr('2*int((@nf + 1)/2) * (@W / @nf + 0.29)')"
as="expr('int((@nf + 2)/2) * @W / @nf * 0.29')"
ps="expr('2*int((@nf + 2)/2) * (@W / @nf + 0.29)')"
nrd="expr('0.29 / @W ')" nrs="expr('0.29 / @W ')"
sa=0 sb=0 sd=0
model=nfet_01v8
spiceprefix=X
}
C {gnd.sym} 1240 -1290 0 1 {name=l32 lab=GND}
C {lab_pin.sym} 1180 -1470 0 0 {name=p121 sig_type=std_logic lab=PRE}
C {sky130_fd_pr/cap_mim_m3_1.sym} 1530 -1320 0 0 {name=C5 model=cap_mim_m3_1 W=90 L=1 MF=1 spiceprefix=X}
C {gnd.sym} 1530 -1520 2 0 {name=l33 lab=GND}
C {sky130_fd_pr/nfet_01v8.sym} 1510 -1470 2 1 {name=M5
W=1
L=0.15
nf=1 
mult=1
ad="expr('int((@nf + 1)/2) * @W / @nf * 0.29')"
pd="expr('2*int((@nf + 1)/2) * (@W / @nf + 0.29)')"
as="expr('int((@nf + 2)/2) * @W / @nf * 0.29')"
ps="expr('2*int((@nf + 2)/2) * (@W / @nf + 0.29)')"
nrd="expr('0.29 / @W ')" nrs="expr('0.29 / @W ')"
sa=0 sb=0 sd=0
model=nfet_01v8
spiceprefix=X
}
C {gnd.sym} 1530 -1290 0 1 {name=l34 lab=GND}
C {lab_pin.sym} 1470 -1470 0 0 {name=p123 sig_type=std_logic lab=PRE}
C {sky130_fd_pr/cap_mim_m3_1.sym} 1820 -1320 0 0 {name=C6 model=cap_mim_m3_1 W=90 L=1 MF=1 spiceprefix=X}
C {gnd.sym} 1820 -1520 2 0 {name=l35 lab=GND}
C {sky130_fd_pr/nfet_01v8.sym} 1800 -1470 2 1 {name=M6
W=1
L=0.15
nf=1 
mult=1
ad="expr('int((@nf + 1)/2) * @W / @nf * 0.29')"
pd="expr('2*int((@nf + 1)/2) * (@W / @nf + 0.29)')"
as="expr('int((@nf + 2)/2) * @W / @nf * 0.29')"
ps="expr('2*int((@nf + 2)/2) * (@W / @nf + 0.29)')"
nrd="expr('0.29 / @W ')" nrs="expr('0.29 / @W ')"
sa=0 sb=0 sd=0
model=nfet_01v8
spiceprefix=X
}
C {gnd.sym} 1820 -1290 0 1 {name=l36 lab=GND}
C {lab_pin.sym} 1760 -1470 0 0 {name=p125 sig_type=std_logic lab=PRE}
C {sky130_fd_pr/cap_mim_m3_1.sym} 2110 -1320 0 0 {name=C7 model=cap_mim_m3_1 W=90 L=1 MF=1 spiceprefix=X}
C {gnd.sym} 2110 -1520 2 0 {name=l37 lab=GND}
C {sky130_fd_pr/nfet_01v8.sym} 2090 -1470 2 1 {name=M7
W=1
L=0.15
nf=1 
mult=1
ad="expr('int((@nf + 1)/2) * @W / @nf * 0.29')"
pd="expr('2*int((@nf + 1)/2) * (@W / @nf + 0.29)')"
as="expr('int((@nf + 2)/2) * @W / @nf * 0.29')"
ps="expr('2*int((@nf + 2)/2) * (@W / @nf + 0.29)')"
nrd="expr('0.29 / @W ')" nrs="expr('0.29 / @W ')"
sa=0 sb=0 sd=0
model=nfet_01v8
spiceprefix=X
}
C {gnd.sym} 2110 -1290 0 1 {name=l38 lab=GND}
C {lab_pin.sym} 2050 -1470 0 0 {name=p127 sig_type=std_logic lab=PRE}
C {sky130_fd_pr/cap_mim_m3_1.sym} 2400 -1320 0 0 {name=C8 model=cap_mim_m3_1 W=90 L=1 MF=1 spiceprefix=X}
C {gnd.sym} 2400 -1520 2 0 {name=l39 lab=GND}
C {sky130_fd_pr/nfet_01v8.sym} 2380 -1470 2 1 {name=M8
W=1
L=0.15
nf=1 
mult=1
ad="expr('int((@nf + 1)/2) * @W / @nf * 0.29')"
pd="expr('2*int((@nf + 1)/2) * (@W / @nf + 0.29)')"
as="expr('int((@nf + 2)/2) * @W / @nf * 0.29')"
ps="expr('2*int((@nf + 2)/2) * (@W / @nf + 0.29)')"
nrd="expr('0.29 / @W ')" nrs="expr('0.29 / @W ')"
sa=0 sb=0 sd=0
model=nfet_01v8
spiceprefix=X
}
C {gnd.sym} 2400 -1290 0 1 {name=l40 lab=GND}
C {lab_pin.sym} 2340 -1470 0 0 {name=p129 sig_type=std_logic lab=PRE}
C {lab_pin.sym} 440 -1380 0 1 {name=p50 sig_type=std_logic lab=RBL7}
C {lab_pin.sym} 730 -1380 0 1 {name=p94 sig_type=std_logic lab=RBL6}
C {lab_pin.sym} 1020 -1380 0 1 {name=p102 sig_type=std_logic lab=RBL5}
C {lab_pin.sym} 1310 -1380 0 1 {name=p120 sig_type=std_logic lab=RBL4}
C {lab_pin.sym} 1600 -1380 0 1 {name=p122 sig_type=std_logic lab=RBL3}
C {lab_pin.sym} 1890 -1380 0 1 {name=p124 sig_type=std_logic lab=RBL2}
C {lab_pin.sym} 2180 -1380 0 1 {name=p126 sig_type=std_logic lab=RBL1}
C {lab_pin.sym} 2470 -1380 0 1 {name=p128 sig_type=std_logic lab=RBL0}
C {voltage_comp/dt-comp_rs_test.sym} 260 -1000 0 0 {name=x17}
C {lab_pin.sym} 410 -1010 0 1 {name=p130 sig_type=std_logic lab=RBL7}
C {iopin.sym} 110 -2100 0 0 {name=p131 lab=CLK}
C {lab_pin.sym} 110 -2100 0 0 {name=p132 sig_type=std_logic lab=CLK}
C {iopin.sym} 110 -2080 0 0 {name=p133 lab=CLK_bar}
C {lab_pin.sym} 110 -2080 0 0 {name=p134 sig_type=std_logic lab=CLK_bar}
C {iopin.sym} 110 -2130 0 0 {name=p135 lab=EN_bar}
C {lab_pin.sym} 110 -2130 0 0 {name=p136 lab=EN_bar}
C {lab_pin.sym} 410 -910 0 1 {name=p137 sig_type=std_logic lab=EN}
C {lab_pin.sym} 410 -930 0 1 {name=p138 lab=EN_bar}
C {lab_pin.sym} 410 -1070 0 1 {name=p139 sig_type=std_logic lab=VSS}
C {lab_pin.sym} 410 -1090 0 1 {name=p140 sig_type=std_logic lab=VCC}
C {lab_pin.sym} 410 -1050 0 1 {name=p141 sig_type=std_logic lab=CLK}
C {lab_pin.sym} 410 -1030 0 1 {name=p142 sig_type=std_logic lab=CLK_bar}
C {lab_pin.sym} 410 -970 0 1 {name=p143 sig_type=std_logic lab=MAC2}
C {lab_pin.sym} 410 -990 0 1 {name=p144 sig_type=std_logic lab=TR2}
